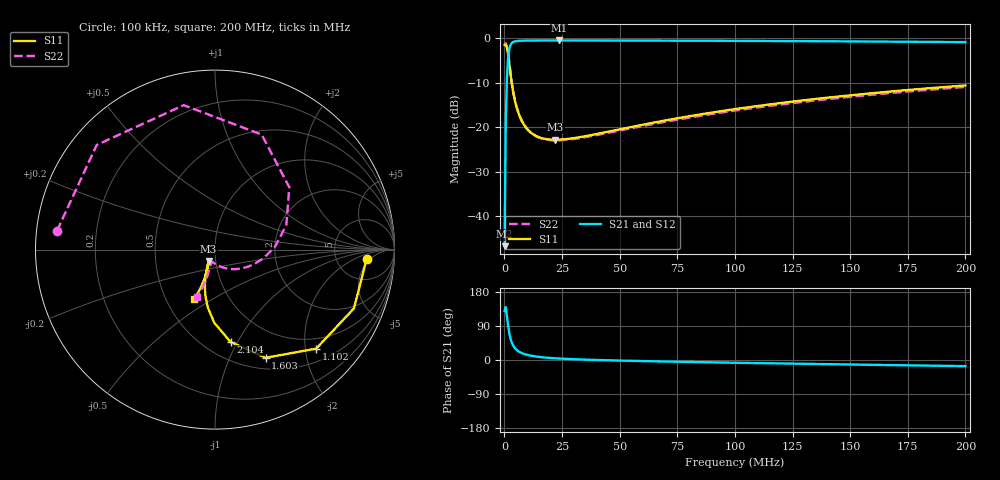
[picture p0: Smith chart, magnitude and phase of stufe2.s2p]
! Created with skrf 2.2.0 (http://scikit-rf.org).
# Hz S MA R 50.0
!freq magS11 angS11 magS21 angS21 magS12 angS12 magS22 angS22
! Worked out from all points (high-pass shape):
!   400 points, 100 kHz to 200 MHz, reference 50 ohm
!   highest |S21| = -0.46 dB at 23.65 MHz (marker M1); lowest = -46.7 dB at 100 kHz (marker M2)
!   |S21| within 3 dB of the highest: 1.865 MHz to end of sweep
!   lowest |S11| = -22.8 dB at 22.14 MHz (marker M3), VSWR 1.16, Z = 46.2 - j5.86 ohm
!   |S11| at or under -10 dB: 3.18 MHz to end of sweep
!   |S22| runs from -22.9 to -1.0 dB; largest |S21 - S12| = 5.2e-16
!   S11 on the Smith chart (normalised r, x): 100 kHz: 10, -4; 1.102 MHz: 0.76, -2.23; 1.603 MHz: 0.63, -1.37; 2.104 MHz: 0.66, -0.94; 200 MHz: 0.69, -0.41
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100000  0.8462 -3.7  0.004605 129.5  0.004605 129.5  0.8868 173.2
601002.5  0.8406 -22.9  0.1159 139.5  0.1159 139.5  0.8798 138.5
1102005  0.7889 -44.4  0.3499 116.0  0.3499 116.0  0.8233 102.2
1603008  0.6653 -64.9  0.5925 91.3  0.5925 91.3  0.6916 67.9
2104010  0.5222 -80.4  0.7519 71.6  0.7519 71.6  0.5404 40.0
2605013  0.4071 -90.6  0.8364 57.6  0.8364 57.6  0.4194 18.7
3106015  0.3253 -97.1  0.8799 47.7  0.8799 47.7  0.3337 2.5
3607018  0.2683 -101.3  0.9035 40.6  0.9035 40.6  0.2741 -10.2
4108020  0.2277 -104.2  0.9172 35.3  0.9172 35.3  0.2318 -20.6
5611028  0.1584 -109.3  0.935 25.2  0.935 25.2  0.1599 -42.8
6613033  0.1338 -111.3  0.9397 21.1  0.9397 21.1  0.1346 -53.2
8116040  0.1112 -113.5  0.9432 16.9  0.9432 16.9  0.1113 -64.8
1.162306e7  0.08665 -116.9  0.9464 11.2  0.9464 11.2  0.08616 -81.9
1.613208e7  0.07568 -119.0  0.9475 7.4  0.9475 7.4  0.0748 -93.6
2.214411e7  0.07255 -119.5  0.9479 4.4  0.9479 4.4  0.0713 -101.1
2.364712e7  0.07271 -119.4  0.9479 3.9  0.9479 3.9  0.07137 -102.1
3.366717e7  0.07825 -117.6  0.9476 1.3  0.9476 1.3  0.07634 -105.6
6.673333e7  0.1155 -111.8  0.9442 -3.7  0.9442 -3.7  0.1116 -106.0
1.003005e8  0.1605 -110.0  0.9382 -7.3  0.9382 -7.3  0.1547 -106.2
1.333667e8  0.2061 -110.2  0.9302 -10.4  0.9302 -10.4  0.1983 -107.3
1.669338e8  0.2519 -111.3  0.9199 -13.4  0.9199 -13.4  0.2423 -109.0
2e8  0.2958 -112.8  0.908 -16.2  0.908 -16.2  0.2844 -110.9
